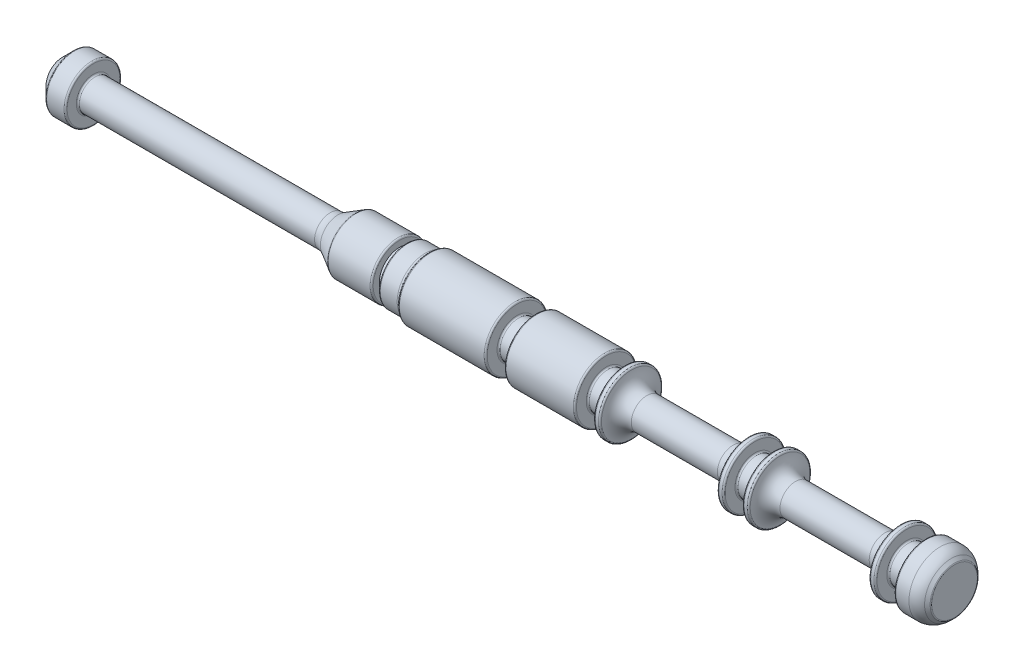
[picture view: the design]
ISO-10303-21;
HEADER;
FILE_DESCRIPTION(('STEP AP214'),'2;1');
FILE_NAME('part.step','',(''),(''),'','','');
FILE_SCHEMA(('AUTOMOTIVE_DESIGN { 1 0 10303 214 1 1 1 1 }'));
ENDSEC;
DATA;
#1=APPLICATION_CONTEXT('core data for automotive mechanical design processes');
#2=APPLICATION_PROTOCOL_DEFINITION('international standard','automotive_design',2000,#1);
#3=PRODUCT_CONTEXT('',#1,'mechanical');
#4=PRODUCT('Part','Part','',(#3));
#5=PRODUCT_RELATED_PRODUCT_CATEGORY('part','',(#4));
#6=PRODUCT_DEFINITION_FORMATION('','',#4);
#7=PRODUCT_DEFINITION_CONTEXT('part definition',#1,'design');
#8=PRODUCT_DEFINITION('design','',#6,#7);
#9=PRODUCT_DEFINITION_SHAPE('','',#8);
#10=(LENGTH_UNIT() NAMED_UNIT(*) SI_UNIT(.MILLI.,.METRE.));
#11=(NAMED_UNIT(*) PLANE_ANGLE_UNIT() SI_UNIT($,.RADIAN.));
#12=(NAMED_UNIT(*) SI_UNIT($,.STERADIAN.) SOLID_ANGLE_UNIT());
#13=UNCERTAINTY_MEASURE_WITH_UNIT(LENGTH_MEASURE(1.E-05),#10,'distance_accuracy_value','');
#14=(GEOMETRIC_REPRESENTATION_CONTEXT(3) GLOBAL_UNCERTAINTY_ASSIGNED_CONTEXT((#13)) GLOBAL_UNIT_ASSIGNED_CONTEXT((#10,
#11,#12)) REPRESENTATION_CONTEXT('',''));
#15=CARTESIAN_POINT('',(0.,0.,0.));
#16=DIRECTION('',(0.,0.,1.));
#17=DIRECTION('',(1.,0.,0.));
#18=AXIS2_PLACEMENT_3D('',#15,#16,#17);
#19=CARTESIAN_POINT('',(12.15,2.,0.));
#20=DIRECTION('',(1.,0.,0.));
#21=DIRECTION('',(0.,0.,-1.));
#22=AXIS2_PLACEMENT_3D('',#19,#20,#21);
#23=PLANE('',#22);
#24=CARTESIAN_POINT('',(12.15,0.,0.));
#25=DIRECTION('',(1.,0.,0.));
#26=DIRECTION('',(0.,0.,-1.));
#27=AXIS2_PLACEMENT_3D('',#24,#25,#26);
#28=CIRCLE('',#27,1.45857864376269);
#29=CARTESIAN_POINT('',(12.15,0.,-1.45857864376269));
#30=VERTEX_POINT('',#29);
#31=EDGE_CURVE('E103',#30,#30,#28,.T.);
#32=ORIENTED_EDGE('',*,*,#31,.T.);
#33=EDGE_LOOP('',(#32));
#34=FACE_BOUND('',#33,.T.);
#35=ADVANCED_FACE('F37',(#34),#23,.T.);
#36=CARTESIAN_POINT('',(0.,0.,0.));
#37=DIRECTION('',(1.,0.,0.));
#38=DIRECTION('',(0.,0.,-1.));
#39=AXIS2_PLACEMENT_3D('',#36,#37,#38);
#40=CYLINDRICAL_SURFACE('',#39,2.);
#41=CARTESIAN_POINT('',(11.2357864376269,0.,0.));
#42=DIRECTION('',(1.,0.,0.));
#43=DIRECTION('',(0.,0.,-1.));
#44=AXIS2_PLACEMENT_3D('',#41,#42,#43);
#45=CIRCLE('',#44,2.);
#46=CARTESIAN_POINT('',(11.2357864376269,0.,-2.));
#47=VERTEX_POINT('',#46);
#48=EDGE_CURVE('E44',#47,#47,#45,.F.);
#49=ORIENTED_EDGE('',*,*,#48,.T.);
#50=EDGE_LOOP('',(#49));
#51=FACE_BOUND('',#50,.T.);
#52=CARTESIAN_POINT('',(10.4,0.,0.));
#53=DIRECTION('',(-1.,0.,0.));
#54=DIRECTION('',(0.,0.,1.));
#55=AXIS2_PLACEMENT_3D('',#52,#53,#54);
#56=CIRCLE('',#55,2.);
#57=CARTESIAN_POINT('',(10.4,0.,2.));
#58=VERTEX_POINT('',#57);
#59=EDGE_CURVE('E52',#58,#58,#56,.F.);
#60=ORIENTED_EDGE('',*,*,#59,.T.);
#61=EDGE_LOOP('',(#60));
#62=FACE_BOUND('',#61,.T.);
#63=ADVANCED_FACE('F284',(#51,#62),#40,.T.);
#64=CARTESIAN_POINT('',(10.3,1.175,0.));
#65=DIRECTION('',(-1.,0.,0.));
#66=DIRECTION('',(0.,0.,1.));
#67=AXIS2_PLACEMENT_3D('',#64,#65,#66);
#68=PLANE('',#67);
#69=CARTESIAN_POINT('',(10.3,0.,0.));
#70=DIRECTION('',(-1.,0.,0.));
#71=DIRECTION('',(0.,0.,1.));
#72=AXIS2_PLACEMENT_3D('',#69,#70,#71);
#73=CIRCLE('',#72,1.9);
#74=CARTESIAN_POINT('',(10.3,0.,1.9));
#75=VERTEX_POINT('',#74);
#76=EDGE_CURVE('E48',#75,#75,#73,.T.);
#77=ORIENTED_EDGE('',*,*,#76,.T.);
#78=EDGE_LOOP('',(#77));
#79=FACE_BOUND('',#78,.T.);
#80=CARTESIAN_POINT('',(10.3,0.,0.));
#81=DIRECTION('',(-1.,0.,0.));
#82=DIRECTION('',(0.,0.,1.));
#83=AXIS2_PLACEMENT_3D('',#80,#81,#82);
#84=CIRCLE('',#83,1.275);
#85=CARTESIAN_POINT('',(10.3,0.,1.275));
#86=VERTEX_POINT('',#85);
#87=EDGE_CURVE('E185',#86,#86,#84,.F.);
#88=ORIENTED_EDGE('',*,*,#87,.T.);
#89=EDGE_LOOP('',(#88));
#90=FACE_BOUND('',#89,.T.);
#91=ADVANCED_FACE('F290',(#79,#90),#68,.T.);
#92=CARTESIAN_POINT('',(0.,0.,0.));
#93=DIRECTION('',(1.,0.,0.));
#94=DIRECTION('',(0.,0.,-1.));
#95=AXIS2_PLACEMENT_3D('',#92,#93,#94);
#96=CYLINDRICAL_SURFACE('',#95,1.175);
#97=CARTESIAN_POINT('',(9.2,0.,0.));
#98=DIRECTION('',(1.,0.,0.));
#99=DIRECTION('',(0.,0.,-1.));
#100=AXIS2_PLACEMENT_3D('',#97,#98,#99);
#101=CIRCLE('',#100,1.175);
#102=CARTESIAN_POINT('',(9.2,0.,-1.175));
#103=VERTEX_POINT('',#102);
#104=EDGE_CURVE('E191',#103,#103,#101,.T.);
#105=ORIENTED_EDGE('',*,*,#104,.T.);
#106=EDGE_LOOP('',(#105));
#107=FACE_BOUND('',#106,.T.);
#108=CARTESIAN_POINT('',(10.2,0.,0.));
#109=DIRECTION('',(-1.,0.,0.));
#110=DIRECTION('',(0.,0.,1.));
#111=AXIS2_PLACEMENT_3D('',#108,#109,#110);
#112=CIRCLE('',#111,1.175);
#113=CARTESIAN_POINT('',(10.2,0.,1.175));
#114=VERTEX_POINT('',#113);
#115=EDGE_CURVE('E194',#114,#114,#112,.T.);
#116=ORIENTED_EDGE('',*,*,#115,.T.);
#117=EDGE_LOOP('',(#116));
#118=FACE_BOUND('',#117,.T.);
#119=ADVANCED_FACE('F451',(#107,#118),#96,.T.);
#120=CARTESIAN_POINT('',(9.1,2.,0.));
#121=DIRECTION('',(1.,0.,0.));
#122=DIRECTION('',(0.,0.,-1.));
#123=AXIS2_PLACEMENT_3D('',#120,#121,#122);
#124=PLANE('',#123);
#125=CARTESIAN_POINT('',(9.1,0.,0.));
#126=DIRECTION('',(1.,0.,0.));
#127=DIRECTION('',(0.,0.,-1.));
#128=AXIS2_PLACEMENT_3D('',#125,#126,#127);
#129=CIRCLE('',#128,1.9);
#130=CARTESIAN_POINT('',(9.1,0.,-1.9));
#131=VERTEX_POINT('',#130);
#132=EDGE_CURVE('E115',#131,#131,#129,.T.);
#133=ORIENTED_EDGE('',*,*,#132,.T.);
#134=EDGE_LOOP('',(#133));
#135=FACE_BOUND('',#134,.T.);
#136=CARTESIAN_POINT('',(9.1,0.,0.));
#137=DIRECTION('',(1.,0.,0.));
#138=DIRECTION('',(0.,0.,-1.));
#139=AXIS2_PLACEMENT_3D('',#136,#137,#138);
#140=CIRCLE('',#139,1.275);
#141=CARTESIAN_POINT('',(9.1,0.,-1.275));
#142=VERTEX_POINT('',#141);
#143=EDGE_CURVE('E188',#142,#142,#140,.F.);
#144=ORIENTED_EDGE('',*,*,#143,.T.);
#145=EDGE_LOOP('',(#144));
#146=FACE_BOUND('',#145,.T.);
#147=ADVANCED_FACE('F457',(#135,#146),#124,.T.);
#148=CARTESIAN_POINT('',(0.,0.,0.));
#149=DIRECTION('',(1.,0.,0.));
#150=DIRECTION('',(0.,0.,-1.));
#151=AXIS2_PLACEMENT_3D('',#148,#149,#150);
#152=CYLINDRICAL_SURFACE('',#151,2.);
#153=CARTESIAN_POINT('',(9.,0.,0.));
#154=DIRECTION('',(1.,0.,0.));
#155=DIRECTION('',(0.,0.,-1.));
#156=AXIS2_PLACEMENT_3D('',#153,#154,#155);
#157=CIRCLE('',#156,2.);
#158=CARTESIAN_POINT('',(9.,0.,-2.));
#159=VERTEX_POINT('',#158);
#160=EDGE_CURVE('E109',#159,#159,#157,.F.);
#161=ORIENTED_EDGE('',*,*,#160,.T.);
#162=EDGE_LOOP('',(#161));
#163=FACE_BOUND('',#162,.T.);
#164=CARTESIAN_POINT('',(8.79544511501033,0.,0.));
#165=DIRECTION('',(-1.,0.,0.));
#166=DIRECTION('',(0.,0.,1.));
#167=AXIS2_PLACEMENT_3D('',#164,#165,#166);
#168=CIRCLE('',#167,2.);
#169=CARTESIAN_POINT('',(8.79544511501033,0.,2.));
#170=VERTEX_POINT('',#169);
#171=EDGE_CURVE('E112',#170,#170,#168,.F.);
#172=ORIENTED_EDGE('',*,*,#171,.T.);
#173=EDGE_LOOP('',(#172));
#174=FACE_BOUND('',#173,.T.);
#175=ADVANCED_FACE('F463',(#163,#174),#152,.T.);
#176=CARTESIAN_POINT('',(0.,0.,0.));
#177=DIRECTION('',(1.,0.,0.));
#178=DIRECTION('',(0.,0.,-1.));
#179=AXIS2_PLACEMENT_3D('',#176,#177,#178);
#180=CYLINDRICAL_SURFACE('',#179,0.999999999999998);
#181=CARTESIAN_POINT('',(7.7,0.,0.));
#182=DIRECTION('',(-1.,0.,0.));
#183=DIRECTION('',(0.,0.,1.));
#184=AXIS2_PLACEMENT_3D('',#181,#182,#183);
#185=CIRCLE('',#184,0.999999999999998);
#186=CARTESIAN_POINT('',(7.7,0.,0.999999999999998));
#187=VERTEX_POINT('',#186);
#188=EDGE_CURVE('E251',#187,#187,#185,.T.);
#189=ORIENTED_EDGE('',*,*,#188,.T.);
#190=EDGE_LOOP('',(#189));
#191=FACE_BOUND('',#190,.T.);
#192=CARTESIAN_POINT('',(2.,0.,0.));
#193=DIRECTION('',(1.,0.,0.));
#194=DIRECTION('',(0.,0.,-1.));
#195=AXIS2_PLACEMENT_3D('',#192,#193,#194);
#196=CIRCLE('',#195,0.999999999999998);
#197=CARTESIAN_POINT('',(2.,0.,-0.999999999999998));
#198=VERTEX_POINT('',#197);
#199=EDGE_CURVE('E254',#198,#198,#196,.T.);
#200=ORIENTED_EDGE('',*,*,#199,.T.);
#201=EDGE_LOOP('',(#200));
#202=FACE_BOUND('',#201,.T.);
#203=ADVANCED_FACE('F467',(#191,#202),#180,.T.);
#204=CARTESIAN_POINT('',(0.,0.,0.));
#205=DIRECTION('',(1.,0.,0.));
#206=DIRECTION('',(0.,0.,-1.));
#207=AXIS2_PLACEMENT_3D('',#204,#205,#206);
#208=CYLINDRICAL_SURFACE('',#207,2.);
#209=CARTESIAN_POINT('',(0.904554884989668,0.,0.));
#210=DIRECTION('',(-1.,0.,0.));
#211=DIRECTION('',(0.,0.,1.));
#212=AXIS2_PLACEMENT_3D('',#209,#210,#211);
#213=CIRCLE('',#212,2.);
#214=CARTESIAN_POINT('',(0.904554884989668,0.,2.));
#215=VERTEX_POINT('',#214);
#216=EDGE_CURVE('E121',#215,#215,#213,.T.);
#217=ORIENTED_EDGE('',*,*,#216,.T.);
#218=EDGE_LOOP('',(#217));
#219=FACE_BOUND('',#218,.T.);
#220=CARTESIAN_POINT('',(0.7,0.,0.));
#221=DIRECTION('',(-1.,0.,0.));
#222=DIRECTION('',(0.,0.,1.));
#223=AXIS2_PLACEMENT_3D('',#220,#221,#222);
#224=CIRCLE('',#223,2.);
#225=CARTESIAN_POINT('',(0.7,0.,2.));
#226=VERTEX_POINT('',#225);
#227=EDGE_CURVE('E124',#226,#226,#224,.F.);
#228=ORIENTED_EDGE('',*,*,#227,.T.);
#229=EDGE_LOOP('',(#228));
#230=FACE_BOUND('',#229,.T.);
#231=ADVANCED_FACE('F471',(#219,#230),#208,.T.);
#232=CARTESIAN_POINT('',(0.6,1.175,0.));
#233=DIRECTION('',(-1.,0.,0.));
#234=DIRECTION('',(0.,0.,1.));
#235=AXIS2_PLACEMENT_3D('',#232,#233,#234);
#236=PLANE('',#235);
#237=CARTESIAN_POINT('',(0.6,0.,0.));
#238=DIRECTION('',(-1.,0.,0.));
#239=DIRECTION('',(0.,0.,1.));
#240=AXIS2_PLACEMENT_3D('',#237,#238,#239);
#241=CIRCLE('',#240,1.9);
#242=CARTESIAN_POINT('',(0.6,0.,1.9));
#243=VERTEX_POINT('',#242);
#244=EDGE_CURVE('E118',#243,#243,#241,.T.);
#245=ORIENTED_EDGE('',*,*,#244,.T.);
#246=EDGE_LOOP('',(#245));
#247=FACE_BOUND('',#246,.T.);
#248=CARTESIAN_POINT('',(0.6,0.,0.));
#249=DIRECTION('',(-1.,0.,0.));
#250=DIRECTION('',(0.,0.,1.));
#251=AXIS2_PLACEMENT_3D('',#248,#249,#250);
#252=CIRCLE('',#251,1.275);
#253=CARTESIAN_POINT('',(0.6,0.,1.275));
#254=VERTEX_POINT('',#253);
#255=EDGE_CURVE('E197',#254,#254,#252,.F.);
#256=ORIENTED_EDGE('',*,*,#255,.T.);
#257=EDGE_LOOP('',(#256));
#258=FACE_BOUND('',#257,.T.);
#259=ADVANCED_FACE('F475',(#247,#258),#236,.T.);
#260=CARTESIAN_POINT('',(0.,0.,0.));
#261=DIRECTION('',(1.,0.,0.));
#262=DIRECTION('',(0.,0.,-1.));
#263=AXIS2_PLACEMENT_3D('',#260,#261,#262);
#264=CYLINDRICAL_SURFACE('',#263,1.175);
#265=CARTESIAN_POINT('',(-0.5,0.,0.));
#266=DIRECTION('',(1.,0.,0.));
#267=DIRECTION('',(0.,0.,-1.));
#268=AXIS2_PLACEMENT_3D('',#265,#266,#267);
#269=CIRCLE('',#268,1.175);
#270=CARTESIAN_POINT('',(-0.5,0.,-1.175));
#271=VERTEX_POINT('',#270);
#272=EDGE_CURVE('E203',#271,#271,#269,.T.);
#273=ORIENTED_EDGE('',*,*,#272,.T.);
#274=EDGE_LOOP('',(#273));
#275=FACE_BOUND('',#274,.T.);
#276=CARTESIAN_POINT('',(0.5,0.,0.));
#277=DIRECTION('',(-1.,0.,0.));
#278=DIRECTION('',(0.,0.,1.));
#279=AXIS2_PLACEMENT_3D('',#276,#277,#278);
#280=CIRCLE('',#279,1.175);
#281=CARTESIAN_POINT('',(0.5,0.,1.175));
#282=VERTEX_POINT('',#281);
#283=EDGE_CURVE('E206',#282,#282,#280,.T.);
#284=ORIENTED_EDGE('',*,*,#283,.T.);
#285=EDGE_LOOP('',(#284));
#286=FACE_BOUND('',#285,.T.);
#287=ADVANCED_FACE('F479',(#275,#286),#264,.T.);
#288=CARTESIAN_POINT('',(-0.6,2.,0.));
#289=DIRECTION('',(1.,0.,0.));
#290=DIRECTION('',(0.,0.,-1.));
#291=AXIS2_PLACEMENT_3D('',#288,#289,#290);
#292=PLANE('',#291);
#293=CARTESIAN_POINT('',(-0.6,0.,0.));
#294=DIRECTION('',(1.,0.,0.));
#295=DIRECTION('',(0.,0.,-1.));
#296=AXIS2_PLACEMENT_3D('',#293,#294,#295);
#297=CIRCLE('',#296,1.9);
#298=CARTESIAN_POINT('',(-0.6,0.,-1.9));
#299=VERTEX_POINT('',#298);
#300=EDGE_CURVE('E139',#299,#299,#297,.T.);
#301=ORIENTED_EDGE('',*,*,#300,.T.);
#302=EDGE_LOOP('',(#301));
#303=FACE_BOUND('',#302,.T.);
#304=CARTESIAN_POINT('',(-0.6,0.,0.));
#305=DIRECTION('',(1.,0.,0.));
#306=DIRECTION('',(0.,0.,-1.));
#307=AXIS2_PLACEMENT_3D('',#304,#305,#306);
#308=CIRCLE('',#307,1.275);
#309=CARTESIAN_POINT('',(-0.6,0.,-1.275));
#310=VERTEX_POINT('',#309);
#311=EDGE_CURVE('E200',#310,#310,#308,.F.);
#312=ORIENTED_EDGE('',*,*,#311,.T.);
#313=EDGE_LOOP('',(#312));
#314=FACE_BOUND('',#313,.T.);
#315=ADVANCED_FACE('F483',(#303,#314),#292,.T.);
#316=CARTESIAN_POINT('',(0.,0.,0.));
#317=DIRECTION('',(1.,0.,0.));
#318=DIRECTION('',(0.,0.,-1.));
#319=AXIS2_PLACEMENT_3D('',#316,#317,#318);
#320=CYLINDRICAL_SURFACE('',#319,2.);
#321=CARTESIAN_POINT('',(-0.7,0.,0.));
#322=DIRECTION('',(1.,0.,0.));
#323=DIRECTION('',(0.,0.,-1.));
#324=AXIS2_PLACEMENT_3D('',#321,#322,#323);
#325=CIRCLE('',#324,2.);
#326=CARTESIAN_POINT('',(-0.7,0.,-2.));
#327=VERTEX_POINT('',#326);
#328=EDGE_CURVE('E133',#327,#327,#325,.F.);
#329=ORIENTED_EDGE('',*,*,#328,.T.);
#330=EDGE_LOOP('',(#329));
#331=FACE_BOUND('',#330,.T.);
#332=CARTESIAN_POINT('',(-0.904554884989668,0.,0.));
#333=DIRECTION('',(-1.,0.,0.));
#334=DIRECTION('',(0.,0.,1.));
#335=AXIS2_PLACEMENT_3D('',#332,#333,#334);
#336=CIRCLE('',#335,2.);
#337=CARTESIAN_POINT('',(-0.904554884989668,0.,2.));
#338=VERTEX_POINT('',#337);
#339=EDGE_CURVE('E136',#338,#338,#336,.F.);
#340=ORIENTED_EDGE('',*,*,#339,.T.);
#341=EDGE_LOOP('',(#340));
#342=FACE_BOUND('',#341,.T.);
#343=ADVANCED_FACE('F487',(#331,#342),#320,.T.);
#344=CARTESIAN_POINT('',(0.,0.,0.));
#345=DIRECTION('',(1.,0.,0.));
#346=DIRECTION('',(0.,0.,-1.));
#347=AXIS2_PLACEMENT_3D('',#344,#345,#346);
#348=CYLINDRICAL_SURFACE('',#347,0.999999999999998);
#349=CARTESIAN_POINT('',(-2.,0.,0.));
#350=DIRECTION('',(-1.,0.,0.));
#351=DIRECTION('',(0.,0.,1.));
#352=AXIS2_PLACEMENT_3D('',#349,#350,#351);
#353=CIRCLE('',#352,0.999999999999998);
#354=CARTESIAN_POINT('',(-2.,0.,0.999999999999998));
#355=VERTEX_POINT('',#354);
#356=EDGE_CURVE('E245',#355,#355,#353,.T.);
#357=ORIENTED_EDGE('',*,*,#356,.T.);
#358=EDGE_LOOP('',(#357));
#359=FACE_BOUND('',#358,.T.);
#360=CARTESIAN_POINT('',(-7.5,0.,0.));
#361=DIRECTION('',(1.,0.,0.));
#362=DIRECTION('',(0.,0.,-1.));
#363=AXIS2_PLACEMENT_3D('',#360,#361,#362);
#364=CIRCLE('',#363,0.999999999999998);
#365=CARTESIAN_POINT('',(-7.5,0.,-0.999999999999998));
#366=VERTEX_POINT('',#365);
#367=EDGE_CURVE('E248',#366,#366,#364,.T.);
#368=ORIENTED_EDGE('',*,*,#367,.T.);
#369=EDGE_LOOP('',(#368));
#370=FACE_BOUND('',#369,.T.);
#371=ADVANCED_FACE('F491',(#359,#370),#348,.T.);
#372=CARTESIAN_POINT('',(0.,0.,0.));
#373=DIRECTION('',(1.,0.,0.));
#374=DIRECTION('',(0.,0.,-1.));
#375=AXIS2_PLACEMENT_3D('',#372,#373,#374);
#376=CYLINDRICAL_SURFACE('',#375,2.);
#377=CARTESIAN_POINT('',(-8.59544511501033,0.,0.));
#378=DIRECTION('',(-1.,0.,0.));
#379=DIRECTION('',(0.,0.,1.));
#380=AXIS2_PLACEMENT_3D('',#377,#378,#379);
#381=CIRCLE('',#380,2.);
#382=CARTESIAN_POINT('',(-8.59544511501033,0.,2.));
#383=VERTEX_POINT('',#382);
#384=EDGE_CURVE('E145',#383,#383,#381,.T.);
#385=ORIENTED_EDGE('',*,*,#384,.T.);
#386=EDGE_LOOP('',(#385));
#387=FACE_BOUND('',#386,.T.);
#388=CARTESIAN_POINT('',(-8.8,0.,0.));
#389=DIRECTION('',(-1.,0.,0.));
#390=DIRECTION('',(0.,0.,1.));
#391=AXIS2_PLACEMENT_3D('',#388,#389,#390);
#392=CIRCLE('',#391,2.);
#393=CARTESIAN_POINT('',(-8.8,0.,2.));
#394=VERTEX_POINT('',#393);
#395=EDGE_CURVE('E148',#394,#394,#392,.F.);
#396=ORIENTED_EDGE('',*,*,#395,.T.);
#397=EDGE_LOOP('',(#396));
#398=FACE_BOUND('',#397,.T.);
#399=ADVANCED_FACE('F495',(#387,#398),#376,.T.);
#400=CARTESIAN_POINT('',(-8.9,1.175,0.));
#401=DIRECTION('',(-1.,0.,0.));
#402=DIRECTION('',(0.,0.,1.));
#403=AXIS2_PLACEMENT_3D('',#400,#401,#402);
#404=PLANE('',#403);
#405=CARTESIAN_POINT('',(-8.9,0.,0.));
#406=DIRECTION('',(-1.,0.,0.));
#407=DIRECTION('',(0.,0.,1.));
#408=AXIS2_PLACEMENT_3D('',#405,#406,#407);
#409=CIRCLE('',#408,1.9);
#410=CARTESIAN_POINT('',(-8.9,0.,1.9));
#411=VERTEX_POINT('',#410);
#412=EDGE_CURVE('E142',#411,#411,#409,.T.);
#413=ORIENTED_EDGE('',*,*,#412,.T.);
#414=EDGE_LOOP('',(#413));
#415=FACE_BOUND('',#414,.T.);
#416=CARTESIAN_POINT('',(-8.9,0.,0.));
#417=DIRECTION('',(-1.,0.,0.));
#418=DIRECTION('',(0.,0.,1.));
#419=AXIS2_PLACEMENT_3D('',#416,#417,#418);
#420=CIRCLE('',#419,1.275);
#421=CARTESIAN_POINT('',(-8.9,0.,1.275));
#422=VERTEX_POINT('',#421);
#423=EDGE_CURVE('E209',#422,#422,#420,.F.);
#424=ORIENTED_EDGE('',*,*,#423,.T.);
#425=EDGE_LOOP('',(#424));
#426=FACE_BOUND('',#425,.T.);
#427=ADVANCED_FACE('F499',(#415,#426),#404,.T.);
#428=CARTESIAN_POINT('',(0.,0.,0.));
#429=DIRECTION('',(1.,0.,0.));
#430=DIRECTION('',(0.,0.,-1.));
#431=AXIS2_PLACEMENT_3D('',#428,#429,#430);
#432=CYLINDRICAL_SURFACE('',#431,1.175);
#433=CARTESIAN_POINT('',(-10.,0.,0.));
#434=DIRECTION('',(1.,0.,0.));
#435=DIRECTION('',(0.,0.,-1.));
#436=AXIS2_PLACEMENT_3D('',#433,#434,#435);
#437=CIRCLE('',#436,1.175);
#438=CARTESIAN_POINT('',(-10.,0.,-1.175));
#439=VERTEX_POINT('',#438);
#440=EDGE_CURVE('E215',#439,#439,#437,.T.);
#441=ORIENTED_EDGE('',*,*,#440,.T.);
#442=EDGE_LOOP('',(#441));
#443=FACE_BOUND('',#442,.T.);
#444=CARTESIAN_POINT('',(-9.,0.,0.));
#445=DIRECTION('',(-1.,0.,0.));
#446=DIRECTION('',(0.,0.,1.));
#447=AXIS2_PLACEMENT_3D('',#444,#445,#446);
#448=CIRCLE('',#447,1.175);
#449=CARTESIAN_POINT('',(-9.,0.,1.175));
#450=VERTEX_POINT('',#449);
#451=EDGE_CURVE('E218',#450,#450,#448,.T.);
#452=ORIENTED_EDGE('',*,*,#451,.T.);
#453=EDGE_LOOP('',(#452));
#454=FACE_BOUND('',#453,.T.);
#455=ADVANCED_FACE('F503',(#443,#454),#432,.T.);
#456=CARTESIAN_POINT('',(-10.1,2.,0.));
#457=DIRECTION('',(1.,0.,0.));
#458=DIRECTION('',(0.,0.,-1.));
#459=AXIS2_PLACEMENT_3D('',#456,#457,#458);
#460=PLANE('',#459);
#461=CARTESIAN_POINT('',(-10.1,0.,0.));
#462=DIRECTION('',(1.,0.,0.));
#463=DIRECTION('',(0.,0.,-1.));
#464=AXIS2_PLACEMENT_3D('',#461,#462,#463);
#465=CIRCLE('',#464,1.9);
#466=CARTESIAN_POINT('',(-10.1,0.,-1.9));
#467=VERTEX_POINT('',#466);
#468=EDGE_CURVE('E163',#467,#467,#465,.T.);
#469=ORIENTED_EDGE('',*,*,#468,.T.);
#470=EDGE_LOOP('',(#469));
#471=FACE_BOUND('',#470,.T.);
#472=CARTESIAN_POINT('',(-10.1,0.,0.));
#473=DIRECTION('',(1.,0.,0.));
#474=DIRECTION('',(0.,0.,-1.));
#475=AXIS2_PLACEMENT_3D('',#472,#473,#474);
#476=CIRCLE('',#475,1.275);
#477=CARTESIAN_POINT('',(-10.1,0.,-1.275));
#478=VERTEX_POINT('',#477);
#479=EDGE_CURVE('E212',#478,#478,#476,.F.);
#480=ORIENTED_EDGE('',*,*,#479,.T.);
#481=EDGE_LOOP('',(#480));
#482=FACE_BOUND('',#481,.T.);
#483=ADVANCED_FACE('F507',(#471,#482),#460,.T.);
#484=CARTESIAN_POINT('',(0.,0.,0.));
#485=DIRECTION('',(1.,0.,0.));
#486=DIRECTION('',(0.,0.,-1.));
#487=AXIS2_PLACEMENT_3D('',#484,#485,#486);
#488=CYLINDRICAL_SURFACE('',#487,2.);
#489=CARTESIAN_POINT('',(-10.2,0.,0.));
#490=DIRECTION('',(1.,0.,0.));
#491=DIRECTION('',(0.,0.,-1.));
#492=AXIS2_PLACEMENT_3D('',#489,#490,#491);
#493=CIRCLE('',#492,2.);
#494=CARTESIAN_POINT('',(-10.2,0.,-2.));
#495=VERTEX_POINT('',#494);
#496=EDGE_CURVE('E157',#495,#495,#493,.F.);
#497=ORIENTED_EDGE('',*,*,#496,.T.);
#498=EDGE_LOOP('',(#497));
#499=FACE_BOUND('',#498,.T.);
#500=CARTESIAN_POINT('',(-14.5,0.,0.));
#501=DIRECTION('',(-1.,0.,0.));
#502=DIRECTION('',(0.,0.,1.));
#503=AXIS2_PLACEMENT_3D('',#500,#501,#502);
#504=CIRCLE('',#503,2.);
#505=CARTESIAN_POINT('',(-14.5,0.,2.));
#506=VERTEX_POINT('',#505);
#507=EDGE_CURVE('E160',#506,#506,#504,.F.);
#508=ORIENTED_EDGE('',*,*,#507,.T.);
#509=EDGE_LOOP('',(#508));
#510=FACE_BOUND('',#509,.T.);
#511=ADVANCED_FACE('F511',(#499,#510),#488,.T.);
#512=CARTESIAN_POINT('',(-14.6,1.175,0.));
#513=DIRECTION('',(-1.,0.,0.));
#514=DIRECTION('',(0.,0.,1.));
#515=AXIS2_PLACEMENT_3D('',#512,#513,#514);
#516=PLANE('',#515);
#517=CARTESIAN_POINT('',(-14.6,0.,0.));
#518=DIRECTION('',(-1.,0.,0.));
#519=DIRECTION('',(0.,0.,1.));
#520=AXIS2_PLACEMENT_3D('',#517,#518,#519);
#521=CIRCLE('',#520,1.9);
#522=CARTESIAN_POINT('',(-14.6,0.,1.9));
#523=VERTEX_POINT('',#522);
#524=EDGE_CURVE('E154',#523,#523,#521,.T.);
#525=ORIENTED_EDGE('',*,*,#524,.T.);
#526=EDGE_LOOP('',(#525));
#527=FACE_BOUND('',#526,.T.);
#528=CARTESIAN_POINT('',(-14.6,0.,0.));
#529=DIRECTION('',(-1.,0.,0.));
#530=DIRECTION('',(0.,0.,1.));
#531=AXIS2_PLACEMENT_3D('',#528,#529,#530);
#532=CIRCLE('',#531,1.275);
#533=CARTESIAN_POINT('',(-14.6,0.,1.275));
#534=VERTEX_POINT('',#533);
#535=EDGE_CURVE('E221',#534,#534,#532,.F.);
#536=ORIENTED_EDGE('',*,*,#535,.T.);
#537=EDGE_LOOP('',(#536));
#538=FACE_BOUND('',#537,.T.);
#539=ADVANCED_FACE('F515',(#527,#538),#516,.T.);
#540=CARTESIAN_POINT('',(0.,0.,0.));
#541=DIRECTION('',(1.,0.,0.));
#542=DIRECTION('',(0.,0.,-1.));
#543=AXIS2_PLACEMENT_3D('',#540,#541,#542);
#544=CYLINDRICAL_SURFACE('',#543,1.175);
#545=CARTESIAN_POINT('',(-15.7,0.,0.));
#546=DIRECTION('',(1.,0.,0.));
#547=DIRECTION('',(0.,0.,-1.));
#548=AXIS2_PLACEMENT_3D('',#545,#546,#547);
#549=CIRCLE('',#548,1.175);
#550=CARTESIAN_POINT('',(-15.7,0.,-1.175));
#551=VERTEX_POINT('',#550);
#552=EDGE_CURVE('E227',#551,#551,#549,.T.);
#553=ORIENTED_EDGE('',*,*,#552,.T.);
#554=EDGE_LOOP('',(#553));
#555=FACE_BOUND('',#554,.T.);
#556=CARTESIAN_POINT('',(-14.7,0.,0.));
#557=DIRECTION('',(-1.,0.,0.));
#558=DIRECTION('',(0.,0.,1.));
#559=AXIS2_PLACEMENT_3D('',#556,#557,#558);
#560=CIRCLE('',#559,1.175);
#561=CARTESIAN_POINT('',(-14.7,0.,1.175));
#562=VERTEX_POINT('',#561);
#563=EDGE_CURVE('E230',#562,#562,#560,.T.);
#564=ORIENTED_EDGE('',*,*,#563,.T.);
#565=EDGE_LOOP('',(#564));
#566=FACE_BOUND('',#565,.T.);
#567=ADVANCED_FACE('F519',(#555,#566),#544,.T.);
#568=CARTESIAN_POINT('',(-15.8,2.,0.));
#569=DIRECTION('',(1.,0.,0.));
#570=DIRECTION('',(0.,0.,-1.));
#571=AXIS2_PLACEMENT_3D('',#568,#569,#570);
#572=PLANE('',#571);
#573=CARTESIAN_POINT('',(-15.8,0.,0.));
#574=DIRECTION('',(1.,0.,0.));
#575=DIRECTION('',(0.,0.,-1.));
#576=AXIS2_PLACEMENT_3D('',#573,#574,#575);
#577=CIRCLE('',#576,1.9);
#578=CARTESIAN_POINT('',(-15.8,0.,-1.9));
#579=VERTEX_POINT('',#578);
#580=EDGE_CURVE('E57',#579,#579,#577,.T.);
#581=ORIENTED_EDGE('',*,*,#580,.T.);
#582=EDGE_LOOP('',(#581));
#583=FACE_BOUND('',#582,.T.);
#584=CARTESIAN_POINT('',(-15.8,0.,0.));
#585=DIRECTION('',(1.,0.,0.));
#586=DIRECTION('',(0.,0.,-1.));
#587=AXIS2_PLACEMENT_3D('',#584,#585,#586);
#588=CIRCLE('',#587,1.275);
#589=CARTESIAN_POINT('',(-15.8,0.,-1.275));
#590=VERTEX_POINT('',#589);
#591=EDGE_CURVE('E224',#590,#590,#588,.F.);
#592=ORIENTED_EDGE('',*,*,#591,.T.);
#593=EDGE_LOOP('',(#592));
#594=FACE_BOUND('',#593,.T.);
#595=ADVANCED_FACE('F523',(#583,#594),#572,.T.);
#596=CARTESIAN_POINT('',(0.,0.,0.));
#597=DIRECTION('',(1.,0.,0.));
#598=DIRECTION('',(0.,0.,-1.));
#599=AXIS2_PLACEMENT_3D('',#596,#597,#598);
#600=CYLINDRICAL_SURFACE('',#599,2.);
#601=CARTESIAN_POINT('',(-21.3085786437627,0.,0.));
#602=DIRECTION('',(-1.,0.,0.));
#603=DIRECTION('',(0.,0.,1.));
#604=AXIS2_PLACEMENT_3D('',#601,#602,#603);
#605=CIRCLE('',#604,2.);
#606=CARTESIAN_POINT('',(-21.3085786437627,0.,2.));
#607=VERTEX_POINT('',#606);
#608=EDGE_CURVE('E170',#607,#607,#605,.F.);
#609=ORIENTED_EDGE('',*,*,#608,.T.);
#610=EDGE_LOOP('',(#609));
#611=FACE_BOUND('',#610,.T.);
#612=CARTESIAN_POINT('',(-15.9,0.,0.));
#613=DIRECTION('',(1.,0.,0.));
#614=DIRECTION('',(0.,0.,-1.));
#615=AXIS2_PLACEMENT_3D('',#612,#613,#614);
#616=CIRCLE('',#615,2.);
#617=CARTESIAN_POINT('',(-15.9,0.,-2.));
#618=VERTEX_POINT('',#617);
#619=EDGE_CURVE('E174',#618,#618,#616,.F.);
#620=ORIENTED_EDGE('',*,*,#619,.T.);
#621=EDGE_LOOP('',(#620));
#622=FACE_BOUND('',#621,.T.);
#623=ADVANCED_FACE('F527',(#611,#622),#600,.T.);
#624=CARTESIAN_POINT('',(-21.35,0.,0.));
#625=DIRECTION('',(1.,0.,0.));
#626=DIRECTION('',(0.,0.,-1.));
#627=AXIS2_PLACEMENT_3D('',#624,#625,#626);
#628=CONICAL_SURFACE('',#627,2.,0.78539816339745);
#629=CARTESIAN_POINT('',(-21.3792893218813,0.,0.));
#630=DIRECTION('',(-1.,0.,0.));
#631=DIRECTION('',(0.,0.,1.));
#632=AXIS2_PLACEMENT_3D('',#629,#630,#631);
#633=CIRCLE('',#632,1.97071067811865);
#634=CARTESIAN_POINT('',(-21.3792893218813,0.,1.97071067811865));
#635=VERTEX_POINT('',#634);
#636=EDGE_CURVE('E166',#635,#635,#633,.T.);
#637=ORIENTED_EDGE('',*,*,#636,.T.);
#638=EDGE_LOOP('',(#637));
#639=FACE_BOUND('',#638,.T.);
#640=CARTESIAN_POINT('',(-21.4908391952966,0.,0.));
#641=DIRECTION('',(1.,0.,0.));
#642=DIRECTION('',(0.,0.,-1.));
#643=AXIS2_PLACEMENT_3D('',#640,#641,#642);
#644=CIRCLE('',#643,1.85916080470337);
#645=CARTESIAN_POINT('',(-21.4908391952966,0.,-1.85916080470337));
#646=VERTEX_POINT('',#645);
#647=EDGE_CURVE('E181',#646,#646,#644,.T.);
#648=ORIENTED_EDGE('',*,*,#647,.T.);
#649=EDGE_LOOP('',(#648));
#650=FACE_BOUND('',#649,.T.);
#651=ADVANCED_FACE('F531',(#639,#650),#628,.T.);
#652=CARTESIAN_POINT('',(0.,0.,0.));
#653=DIRECTION('',(1.,0.,0.));
#654=DIRECTION('',(0.,0.,-1.));
#655=AXIS2_PLACEMENT_3D('',#652,#653,#654);
#656=CYLINDRICAL_SURFACE('',#655,1.7859375);
#657=CARTESIAN_POINT('',(-22.75,0.,0.));
#658=DIRECTION('',(-1.,0.,0.));
#659=DIRECTION('',(0.,0.,1.));
#660=AXIS2_PLACEMENT_3D('',#657,#658,#659);
#661=CIRCLE('',#660,1.7859375);
#662=CARTESIAN_POINT('',(-22.75,0.,1.7859375));
#663=VERTEX_POINT('',#662);
#664=EDGE_CURVE('E64',#663,#663,#661,.F.);
#665=ORIENTED_EDGE('',*,*,#664,.T.);
#666=EDGE_LOOP('',(#665));
#667=FACE_BOUND('',#666,.T.);
#668=CARTESIAN_POINT('',(-21.6676158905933,0.,0.));
#669=DIRECTION('',(1.,0.,0.));
#670=DIRECTION('',(0.,0.,-1.));
#671=AXIS2_PLACEMENT_3D('',#668,#669,#670);
#672=CIRCLE('',#671,1.7859375);
#673=CARTESIAN_POINT('',(-21.6676158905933,0.,-1.7859375));
#674=VERTEX_POINT('',#673);
#675=EDGE_CURVE('E177',#674,#674,#672,.F.);
#676=ORIENTED_EDGE('',*,*,#675,.T.);
#677=EDGE_LOOP('',(#676));
#678=FACE_BOUND('',#677,.T.);
#679=ADVANCED_FACE('F535',(#667,#678),#656,.T.);
#680=CARTESIAN_POINT('',(-22.85,1.7859375,0.));
#681=DIRECTION('',(-1.,0.,0.));
#682=DIRECTION('',(0.,0.,1.));
#683=AXIS2_PLACEMENT_3D('',#680,#681,#682);
#684=PLANE('',#683);
#685=CARTESIAN_POINT('',(-22.85,0.,0.));
#686=DIRECTION('',(-1.,0.,0.));
#687=DIRECTION('',(0.,0.,1.));
#688=AXIS2_PLACEMENT_3D('',#685,#686,#687);
#689=CIRCLE('',#688,1.6859375);
#690=CARTESIAN_POINT('',(-22.85,0.,1.6859375));
#691=VERTEX_POINT('',#690);
#692=EDGE_CURVE('E60',#691,#691,#689,.T.);
#693=ORIENTED_EDGE('',*,*,#692,.T.);
#694=EDGE_LOOP('',(#693));
#695=FACE_BOUND('',#694,.T.);
#696=CARTESIAN_POINT('',(-22.85,0.,0.));
#697=DIRECTION('',(1.,0.,0.));
#698=DIRECTION('',(0.,0.,-1.));
#699=AXIS2_PLACEMENT_3D('',#696,#697,#698);
#700=CIRCLE('',#699,1.2954);
#701=CARTESIAN_POINT('',(-22.85,0.,-1.2954));
#702=VERTEX_POINT('',#701);
#703=EDGE_CURVE('E257',#702,#702,#700,.T.);
#704=ORIENTED_EDGE('',*,*,#703,.T.);
#705=EDGE_LOOP('',(#704));
#706=FACE_BOUND('',#705,.T.);
#707=ADVANCED_FACE('F281',(#695,#706),#684,.T.);
#708=CARTESIAN_POINT('',(0.,0.,0.));
#709=DIRECTION('',(1.,0.,0.));
#710=DIRECTION('',(0.,0.,-1.));
#711=AXIS2_PLACEMENT_3D('',#708,#709,#710);
#712=CYLINDRICAL_SURFACE('',#711,1.2954);
#713=CARTESIAN_POINT('',(-23.3,0.,0.));
#714=DIRECTION('',(1.,0.,0.));
#715=DIRECTION('',(0.,0.,-1.));
#716=AXIS2_PLACEMENT_3D('',#713,#714,#715);
#717=CIRCLE('',#716,1.2954);
#718=CARTESIAN_POINT('',(-23.3,0.,-1.2954));
#719=VERTEX_POINT('',#718);
#720=EDGE_CURVE('E261',#719,#719,#717,.T.);
#721=ORIENTED_EDGE('',*,*,#720,.T.);
#722=EDGE_LOOP('',(#721));
#723=FACE_BOUND('',#722,.T.);
#724=ORIENTED_EDGE('',*,*,#703,.F.);
#725=EDGE_LOOP('',(#724));
#726=FACE_BOUND('',#725,.T.);
#727=ADVANCED_FACE('F266',(#723,#726),#712,.T.);
#728=CARTESIAN_POINT('',(-23.3,1.2954,0.));
#729=DIRECTION('',(1.,0.,0.));
#730=DIRECTION('',(0.,0.,-1.));
#731=AXIS2_PLACEMENT_3D('',#728,#729,#730);
#732=PLANE('',#731);
#733=CARTESIAN_POINT('',(-23.3,0.,0.));
#734=DIRECTION('',(1.,0.,0.));
#735=DIRECTION('',(0.,0.,-1.));
#736=AXIS2_PLACEMENT_3D('',#733,#734,#735);
#737=CIRCLE('',#736,1.6859375);
#738=CARTESIAN_POINT('',(-23.3,0.,-1.6859375));
#739=VERTEX_POINT('',#738);
#740=EDGE_CURVE('E68',#739,#739,#737,.T.);
#741=ORIENTED_EDGE('',*,*,#740,.T.);
#742=EDGE_LOOP('',(#741));
#743=FACE_BOUND('',#742,.T.);
#744=ORIENTED_EDGE('',*,*,#720,.F.);
#745=EDGE_LOOP('',(#744));
#746=FACE_BOUND('',#745,.T.);
#747=ADVANCED_FACE('F269',(#743,#746),#732,.T.);
#748=CARTESIAN_POINT('',(0.,0.,0.));
#749=DIRECTION('',(1.,0.,0.));
#750=DIRECTION('',(0.,0.,-1.));
#751=AXIS2_PLACEMENT_3D('',#748,#749,#750);
#752=CYLINDRICAL_SURFACE('',#751,1.7859375);
#753=CARTESIAN_POINT('',(-26.0732050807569,0.,0.));
#754=DIRECTION('',(-1.,0.,0.));
#755=DIRECTION('',(0.,0.,1.));
#756=AXIS2_PLACEMENT_3D('',#753,#754,#755);
#757=CIRCLE('',#756,1.7859375);
#758=CARTESIAN_POINT('',(-26.0732050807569,0.,1.7859375));
#759=VERTEX_POINT('',#758);
#760=EDGE_CURVE('E84',#759,#759,#757,.F.);
#761=ORIENTED_EDGE('',*,*,#760,.T.);
#762=EDGE_LOOP('',(#761));
#763=FACE_BOUND('',#762,.T.);
#764=CARTESIAN_POINT('',(-23.4,0.,0.));
#765=DIRECTION('',(1.,0.,0.));
#766=DIRECTION('',(0.,0.,-1.));
#767=AXIS2_PLACEMENT_3D('',#764,#765,#766);
#768=CIRCLE('',#767,1.7859375);
#769=CARTESIAN_POINT('',(-23.4,0.,-1.7859375));
#770=VERTEX_POINT('',#769);
#771=EDGE_CURVE('E87',#770,#770,#768,.F.);
#772=ORIENTED_EDGE('',*,*,#771,.T.);
#773=EDGE_LOOP('',(#772));
#774=FACE_BOUND('',#773,.T.);
#775=ADVANCED_FACE('F271',(#763,#774),#752,.T.);
#776=CARTESIAN_POINT('',(-26.1,0.,0.));
#777=DIRECTION('',(1.,0.,0.));
#778=DIRECTION('',(0.,0.,-1.));
#779=AXIS2_PLACEMENT_3D('',#776,#777,#778);
#780=CONICAL_SURFACE('',#779,1.7859375,0.5235987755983);
#781=CARTESIAN_POINT('',(-26.1232050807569,0.,0.));
#782=DIRECTION('',(-1.,0.,0.));
#783=DIRECTION('',(0.,0.,1.));
#784=AXIS2_PLACEMENT_3D('',#781,#782,#783);
#785=CIRCLE('',#784,1.77254004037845);
#786=CARTESIAN_POINT('',(-26.1232050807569,0.,1.77254004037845));
#787=VERTEX_POINT('',#786);
#788=EDGE_CURVE('E81',#787,#787,#785,.T.);
#789=ORIENTED_EDGE('',*,*,#788,.T.);
#790=EDGE_LOOP('',(#789));
#791=FACE_BOUND('',#790,.T.);
#792=CARTESIAN_POINT('',(-27.2292328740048,0.,0.));
#793=DIRECTION('',(1.,0.,0.));
#794=DIRECTION('',(0.,0.,-1.));
#795=AXIS2_PLACEMENT_3D('',#792,#793,#794);
#796=CIRCLE('',#795,1.13397459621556);
#797=CARTESIAN_POINT('',(-27.2292328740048,0.,-1.13397459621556));
#798=VERTEX_POINT('',#797);
#799=EDGE_CURVE('E242',#798,#798,#796,.T.);
#800=ORIENTED_EDGE('',*,*,#799,.T.);
#801=EDGE_LOOP('',(#800));
#802=FACE_BOUND('',#801,.T.);
#803=ADVANCED_FACE('F278',(#791,#802),#780,.T.);
#804=CARTESIAN_POINT('',(0.,0.,0.));
#805=DIRECTION('',(1.,0.,0.));
#806=DIRECTION('',(0.,0.,-1.));
#807=AXIS2_PLACEMENT_3D('',#804,#805,#806);
#808=CYLINDRICAL_SURFACE('',#807,0.999999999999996);
#809=CARTESIAN_POINT('',(-42.75,0.,0.));
#810=DIRECTION('',(1.,0.,0.));
#811=DIRECTION('',(0.,0.,-1.));
#812=AXIS2_PLACEMENT_3D('',#809,#810,#811);
#813=CIRCLE('',#812,0.999999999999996);
#814=CARTESIAN_POINT('',(-42.75,0.,-0.999999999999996));
#815=VERTEX_POINT('',#814);
#816=EDGE_CURVE('E236',#815,#815,#813,.T.);
#817=ORIENTED_EDGE('',*,*,#816,.T.);
#818=EDGE_LOOP('',(#817));
#819=FACE_BOUND('',#818,.T.);
#820=CARTESIAN_POINT('',(-27.7292328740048,0.,0.));
#821=DIRECTION('',(1.,0.,0.));
#822=DIRECTION('',(0.,0.,-1.));
#823=AXIS2_PLACEMENT_3D('',#820,#821,#822);
#824=CIRCLE('',#823,0.999999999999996);
#825=CARTESIAN_POINT('',(-27.7292328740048,0.,-0.999999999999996));
#826=VERTEX_POINT('',#825);
#827=EDGE_CURVE('E239',#826,#826,#824,.F.);
#828=ORIENTED_EDGE('',*,*,#827,.T.);
#829=EDGE_LOOP('',(#828));
#830=FACE_BOUND('',#829,.T.);
#831=ADVANCED_FACE('F819',(#819,#830),#808,.T.);
#832=CARTESIAN_POINT('',(-42.85,0.999999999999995,0.));
#833=DIRECTION('',(1.,0.,0.));
#834=DIRECTION('',(0.,0.,-1.));
#835=AXIS2_PLACEMENT_3D('',#832,#833,#834);
#836=PLANE('',#835);
#837=CARTESIAN_POINT('',(-42.85,0.,0.));
#838=DIRECTION('',(1.,0.,0.));
#839=DIRECTION('',(0.,0.,-1.));
#840=AXIS2_PLACEMENT_3D('',#837,#838,#839);
#841=CIRCLE('',#840,1.6859375);
#842=CARTESIAN_POINT('',(-42.85,0.,-1.6859375));
#843=VERTEX_POINT('',#842);
#844=EDGE_CURVE('E72',#843,#843,#841,.T.);
#845=ORIENTED_EDGE('',*,*,#844,.T.);
#846=EDGE_LOOP('',(#845));
#847=FACE_BOUND('',#846,.T.);
#848=CARTESIAN_POINT('',(-42.85,0.,0.));
#849=DIRECTION('',(1.,0.,0.));
#850=DIRECTION('',(0.,0.,-1.));
#851=AXIS2_PLACEMENT_3D('',#848,#849,#850);
#852=CIRCLE('',#851,1.1);
#853=CARTESIAN_POINT('',(-42.85,0.,-1.1));
#854=VERTEX_POINT('',#853);
#855=EDGE_CURVE('E233',#854,#854,#852,.F.);
#856=ORIENTED_EDGE('',*,*,#855,.T.);
#857=EDGE_LOOP('',(#856));
#858=FACE_BOUND('',#857,.T.);
#859=ADVANCED_FACE('F810',(#847,#858),#836,.T.);
#860=CARTESIAN_POINT('',(0.,0.,0.));
#861=DIRECTION('',(1.,0.,0.));
#862=DIRECTION('',(0.,0.,-1.));
#863=AXIS2_PLACEMENT_3D('',#860,#861,#862);
#864=CYLINDRICAL_SURFACE('',#863,1.7859375);
#865=CARTESIAN_POINT('',(-44.0585786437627,0.,0.));
#866=DIRECTION('',(-1.,0.,0.));
#867=DIRECTION('',(0.,0.,1.));
#868=AXIS2_PLACEMENT_3D('',#865,#866,#867);
#869=CIRCLE('',#868,1.7859375);
#870=CARTESIAN_POINT('',(-44.0585786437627,0.,1.7859375));
#871=VERTEX_POINT('',#870);
#872=EDGE_CURVE('E75',#871,#871,#869,.F.);
#873=ORIENTED_EDGE('',*,*,#872,.T.);
#874=EDGE_LOOP('',(#873));
#875=FACE_BOUND('',#874,.T.);
#876=CARTESIAN_POINT('',(-42.95,0.,0.));
#877=DIRECTION('',(1.,0.,0.));
#878=DIRECTION('',(0.,0.,-1.));
#879=AXIS2_PLACEMENT_3D('',#876,#877,#878);
#880=CIRCLE('',#879,1.7859375);
#881=CARTESIAN_POINT('',(-42.95,0.,-1.7859375));
#882=VERTEX_POINT('',#881);
#883=EDGE_CURVE('E78',#882,#882,#880,.F.);
#884=ORIENTED_EDGE('',*,*,#883,.T.);
#885=EDGE_LOOP('',(#884));
#886=FACE_BOUND('',#885,.T.);
#887=ADVANCED_FACE('F801',(#875,#886),#864,.T.);
#888=CARTESIAN_POINT('',(-44.85,1.7859375,0.));
#889=DIRECTION('',(-1.,0.,0.));
#890=DIRECTION('',(0.,0.,1.));
#891=AXIS2_PLACEMENT_3D('',#888,#889,#890);
#892=PLANE('',#891);
#893=CARTESIAN_POINT('',(-44.85,0.,0.));
#894=DIRECTION('',(-1.,0.,0.));
#895=DIRECTION('',(0.,0.,1.));
#896=AXIS2_PLACEMENT_3D('',#893,#894,#895);
#897=CIRCLE('',#896,0.994516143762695);
#898=CARTESIAN_POINT('',(-44.85,0.,0.994516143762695));
#899=VERTEX_POINT('',#898);
#900=EDGE_CURVE('E97',#899,#899,#897,.T.);
#901=ORIENTED_EDGE('',*,*,#900,.T.);
#902=EDGE_LOOP('',(#901));
#903=FACE_BOUND('',#902,.T.);
#904=ADVANCED_FACE('F298',(#903),#892,.T.);
#905=CARTESIAN_POINT('',(7.7,0.,0.));
#906=DIRECTION('',(-1.,0.,0.));
#907=DIRECTION('',(0.,0.,1.));
#908=AXIS2_PLACEMENT_3D('',#905,#906,#907);
#909=TOROIDAL_SURFACE('',#908,2.,1.);
#910=CARTESIAN_POINT('',(8.69585919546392,0.,0.));
#911=DIRECTION('',(-1.,0.,0.));
#912=DIRECTION('',(0.,0.,1.));
#913=AXIS2_PLACEMENT_3D('',#910,#911,#912);
#914=CIRCLE('',#913,1.90909090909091);
#915=CARTESIAN_POINT('',(8.69585919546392,0.,1.90909090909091));
#916=VERTEX_POINT('',#915);
#917=EDGE_CURVE('E106',#916,#916,#914,.T.);
#918=ORIENTED_EDGE('',*,*,#917,.T.);
#919=EDGE_LOOP('',(#918));
#920=FACE_BOUND('',#919,.T.);
#921=ORIENTED_EDGE('',*,*,#188,.F.);
#922=EDGE_LOOP('',(#921));
#923=FACE_BOUND('',#922,.T.);
#924=ADVANCED_FACE('F294',(#920,#923),#909,.F.);
#925=CARTESIAN_POINT('',(2.,0.,0.));
#926=DIRECTION('',(1.,0.,0.));
#927=DIRECTION('',(0.,0.,-1.));
#928=AXIS2_PLACEMENT_3D('',#925,#926,#927);
#929=TOROIDAL_SURFACE('',#928,2.,1.);
#930=CARTESIAN_POINT('',(1.00414080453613,0.,0.));
#931=DIRECTION('',(1.,0.,0.));
#932=DIRECTION('',(0.,0.,-1.));
#933=AXIS2_PLACEMENT_3D('',#930,#931,#932);
#934=CIRCLE('',#933,1.90909090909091);
#935=CARTESIAN_POINT('',(1.00414080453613,0.,-1.90909090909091));
#936=VERTEX_POINT('',#935);
#937=EDGE_CURVE('E127',#936,#936,#934,.T.);
#938=ORIENTED_EDGE('',*,*,#937,.T.);
#939=EDGE_LOOP('',(#938));
#940=FACE_BOUND('',#939,.T.);
#941=ORIENTED_EDGE('',*,*,#199,.F.);
#942=EDGE_LOOP('',(#941));
#943=FACE_BOUND('',#942,.T.);
#944=ADVANCED_FACE('F297',(#940,#943),#929,.F.);
#945=CARTESIAN_POINT('',(-2.,0.,0.));
#946=DIRECTION('',(-1.,0.,0.));
#947=DIRECTION('',(0.,0.,1.));
#948=AXIS2_PLACEMENT_3D('',#945,#946,#947);
#949=TOROIDAL_SURFACE('',#948,2.,1.);
#950=CARTESIAN_POINT('',(-1.00414080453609,0.,0.));
#951=DIRECTION('',(-1.,0.,0.));
#952=DIRECTION('',(0.,0.,1.));
#953=AXIS2_PLACEMENT_3D('',#950,#951,#952);
#954=CIRCLE('',#953,1.90909090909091);
#955=CARTESIAN_POINT('',(-1.00414080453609,0.,1.90909090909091));
#956=VERTEX_POINT('',#955);
#957=EDGE_CURVE('E130',#956,#956,#954,.T.);
#958=ORIENTED_EDGE('',*,*,#957,.T.);
#959=EDGE_LOOP('',(#958));
#960=FACE_BOUND('',#959,.T.);
#961=ORIENTED_EDGE('',*,*,#356,.F.);
#962=EDGE_LOOP('',(#961));
#963=FACE_BOUND('',#962,.T.);
#964=ADVANCED_FACE('F302',(#960,#963),#949,.F.);
#965=CARTESIAN_POINT('',(-7.5,0.,0.));
#966=DIRECTION('',(1.,0.,0.));
#967=DIRECTION('',(0.,0.,-1.));
#968=AXIS2_PLACEMENT_3D('',#965,#966,#967);
#969=TOROIDAL_SURFACE('',#968,2.,1.);
#970=CARTESIAN_POINT('',(-8.49585919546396,0.,0.));
#971=DIRECTION('',(1.,0.,0.));
#972=DIRECTION('',(0.,0.,-1.));
#973=AXIS2_PLACEMENT_3D('',#970,#971,#972);
#974=CIRCLE('',#973,1.9090909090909);
#975=CARTESIAN_POINT('',(-8.49585919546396,0.,-1.9090909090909));
#976=VERTEX_POINT('',#975);
#977=EDGE_CURVE('E151',#976,#976,#974,.T.);
#978=ORIENTED_EDGE('',*,*,#977,.T.);
#979=EDGE_LOOP('',(#978));
#980=FACE_BOUND('',#979,.T.);
#981=ORIENTED_EDGE('',*,*,#367,.F.);
#982=EDGE_LOOP('',(#981));
#983=FACE_BOUND('',#982,.T.);
#984=ADVANCED_FACE('F306',(#980,#983),#969,.F.);
#985=CARTESIAN_POINT('',(-27.7292328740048,0.,0.));
#986=DIRECTION('',(1.,0.,0.));
#987=DIRECTION('',(0.,0.,-1.));
#988=AXIS2_PLACEMENT_3D('',#985,#986,#987);
#989=TOROIDAL_SURFACE('',#988,2.,1.);
#990=ORIENTED_EDGE('',*,*,#827,.F.);
#991=EDGE_LOOP('',(#990));
#992=FACE_BOUND('',#991,.T.);
#993=ORIENTED_EDGE('',*,*,#799,.F.);
#994=EDGE_LOOP('',(#993));
#995=FACE_BOUND('',#994,.T.);
#996=ADVANCED_FACE('F310',(#992,#995),#989,.F.);
#997=CARTESIAN_POINT('',(-42.75,0.,0.));
#998=DIRECTION('',(1.,0.,0.));
#999=DIRECTION('',(0.,0.,-1.));
#1000=AXIS2_PLACEMENT_3D('',#997,#998,#999);
#1001=TOROIDAL_SURFACE('',#1000,1.1,0.1);
#1002=ORIENTED_EDGE('',*,*,#855,.F.);
#1003=EDGE_LOOP('',(#1002));
#1004=FACE_BOUND('',#1003,.T.);
#1005=ORIENTED_EDGE('',*,*,#816,.F.);
#1006=EDGE_LOOP('',(#1005));
#1007=FACE_BOUND('',#1006,.T.);
#1008=ADVANCED_FACE('F314',(#1004,#1007),#1001,.F.);
#1009=CARTESIAN_POINT('',(-15.7,0.,0.));
#1010=DIRECTION('',(1.,0.,0.));
#1011=DIRECTION('',(0.,0.,-1.));
#1012=AXIS2_PLACEMENT_3D('',#1009,#1010,#1011);
#1013=TOROIDAL_SURFACE('',#1012,1.275,0.1);
#1014=ORIENTED_EDGE('',*,*,#591,.F.);
#1015=EDGE_LOOP('',(#1014));
#1016=FACE_BOUND('',#1015,.T.);
#1017=ORIENTED_EDGE('',*,*,#552,.F.);
#1018=EDGE_LOOP('',(#1017));
#1019=FACE_BOUND('',#1018,.T.);
#1020=ADVANCED_FACE('F318',(#1016,#1019),#1013,.F.);
#1021=CARTESIAN_POINT('',(-14.7,0.,0.));
#1022=DIRECTION('',(-1.,0.,0.));
#1023=DIRECTION('',(0.,0.,1.));
#1024=AXIS2_PLACEMENT_3D('',#1021,#1022,#1023);
#1025=TOROIDAL_SURFACE('',#1024,1.275,0.1);
#1026=ORIENTED_EDGE('',*,*,#563,.F.);
#1027=EDGE_LOOP('',(#1026));
#1028=FACE_BOUND('',#1027,.T.);
#1029=ORIENTED_EDGE('',*,*,#535,.F.);
#1030=EDGE_LOOP('',(#1029));
#1031=FACE_BOUND('',#1030,.T.);
#1032=ADVANCED_FACE('F322',(#1028,#1031),#1025,.F.);
#1033=CARTESIAN_POINT('',(-10.,0.,0.));
#1034=DIRECTION('',(1.,0.,0.));
#1035=DIRECTION('',(0.,0.,-1.));
#1036=AXIS2_PLACEMENT_3D('',#1033,#1034,#1035);
#1037=TOROIDAL_SURFACE('',#1036,1.275,0.1);
#1038=ORIENTED_EDGE('',*,*,#479,.F.);
#1039=EDGE_LOOP('',(#1038));
#1040=FACE_BOUND('',#1039,.T.);
#1041=ORIENTED_EDGE('',*,*,#440,.F.);
#1042=EDGE_LOOP('',(#1041));
#1043=FACE_BOUND('',#1042,.T.);
#1044=ADVANCED_FACE('F326',(#1040,#1043),#1037,.F.);
#1045=CARTESIAN_POINT('',(-9.,0.,0.));
#1046=DIRECTION('',(-1.,0.,0.));
#1047=DIRECTION('',(0.,0.,1.));
#1048=AXIS2_PLACEMENT_3D('',#1045,#1046,#1047);
#1049=TOROIDAL_SURFACE('',#1048,1.275,0.1);
#1050=ORIENTED_EDGE('',*,*,#451,.F.);
#1051=EDGE_LOOP('',(#1050));
#1052=FACE_BOUND('',#1051,.T.);
#1053=ORIENTED_EDGE('',*,*,#423,.F.);
#1054=EDGE_LOOP('',(#1053));
#1055=FACE_BOUND('',#1054,.T.);
#1056=ADVANCED_FACE('F330',(#1052,#1055),#1049,.F.);
#1057=CARTESIAN_POINT('',(-0.5,0.,0.));
#1058=DIRECTION('',(1.,0.,0.));
#1059=DIRECTION('',(0.,0.,-1.));
#1060=AXIS2_PLACEMENT_3D('',#1057,#1058,#1059);
#1061=TOROIDAL_SURFACE('',#1060,1.275,0.1);
#1062=ORIENTED_EDGE('',*,*,#311,.F.);
#1063=EDGE_LOOP('',(#1062));
#1064=FACE_BOUND('',#1063,.T.);
#1065=ORIENTED_EDGE('',*,*,#272,.F.);
#1066=EDGE_LOOP('',(#1065));
#1067=FACE_BOUND('',#1066,.T.);
#1068=ADVANCED_FACE('F334',(#1064,#1067),#1061,.F.);
#1069=CARTESIAN_POINT('',(0.5,0.,0.));
#1070=DIRECTION('',(-1.,0.,0.));
#1071=DIRECTION('',(0.,0.,1.));
#1072=AXIS2_PLACEMENT_3D('',#1069,#1070,#1071);
#1073=TOROIDAL_SURFACE('',#1072,1.275,0.1);
#1074=ORIENTED_EDGE('',*,*,#283,.F.);
#1075=EDGE_LOOP('',(#1074));
#1076=FACE_BOUND('',#1075,.T.);
#1077=ORIENTED_EDGE('',*,*,#255,.F.);
#1078=EDGE_LOOP('',(#1077));
#1079=FACE_BOUND('',#1078,.T.);
#1080=ADVANCED_FACE('F338',(#1076,#1079),#1073,.F.);
#1081=CARTESIAN_POINT('',(9.2,0.,0.));
#1082=DIRECTION('',(1.,0.,0.));
#1083=DIRECTION('',(0.,0.,-1.));
#1084=AXIS2_PLACEMENT_3D('',#1081,#1082,#1083);
#1085=TOROIDAL_SURFACE('',#1084,1.275,0.1);
#1086=ORIENTED_EDGE('',*,*,#143,.F.);
#1087=EDGE_LOOP('',(#1086));
#1088=FACE_BOUND('',#1087,.T.);
#1089=ORIENTED_EDGE('',*,*,#104,.F.);
#1090=EDGE_LOOP('',(#1089));
#1091=FACE_BOUND('',#1090,.T.);
#1092=ADVANCED_FACE('F342',(#1088,#1091),#1085,.F.);
#1093=CARTESIAN_POINT('',(10.2,0.,0.));
#1094=DIRECTION('',(-1.,0.,0.));
#1095=DIRECTION('',(0.,0.,1.));
#1096=AXIS2_PLACEMENT_3D('',#1093,#1094,#1095);
#1097=TOROIDAL_SURFACE('',#1096,1.275,0.1);
#1098=ORIENTED_EDGE('',*,*,#115,.F.);
#1099=EDGE_LOOP('',(#1098));
#1100=FACE_BOUND('',#1099,.T.);
#1101=ORIENTED_EDGE('',*,*,#87,.F.);
#1102=EDGE_LOOP('',(#1101));
#1103=FACE_BOUND('',#1102,.T.);
#1104=ADVANCED_FACE('F346',(#1100,#1103),#1097,.F.);
#1105=CARTESIAN_POINT('',(-21.6676158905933,0.,0.));
#1106=DIRECTION('',(1.,0.,0.));
#1107=DIRECTION('',(0.,0.,-1.));
#1108=AXIS2_PLACEMENT_3D('',#1105,#1106,#1107);
#1109=TOROIDAL_SURFACE('',#1108,2.0359375,0.25);
#1110=ORIENTED_EDGE('',*,*,#675,.F.);
#1111=EDGE_LOOP('',(#1110));
#1112=FACE_BOUND('',#1111,.T.);
#1113=ORIENTED_EDGE('',*,*,#647,.F.);
#1114=EDGE_LOOP('',(#1113));
#1115=FACE_BOUND('',#1114,.T.);
#1116=ADVANCED_FACE('F350',(#1112,#1115),#1109,.F.);
#1117=CARTESIAN_POINT('',(-44.1,0.,0.));
#1118=DIRECTION('',(1.,0.,0.));
#1119=DIRECTION('',(0.,0.,-1.));
#1120=AXIS2_PLACEMENT_3D('',#1117,#1118,#1119);
#1121=CONICAL_SURFACE('',#1120,1.7859375,0.785398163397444);
#1122=CARTESIAN_POINT('',(-44.8207106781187,0.,0.));
#1123=DIRECTION('',(-1.,0.,0.));
#1124=DIRECTION('',(0.,0.,1.));
#1125=AXIS2_PLACEMENT_3D('',#1122,#1123,#1124);
#1126=CIRCLE('',#1125,1.06522682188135);
#1127=CARTESIAN_POINT('',(-44.8207106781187,0.,1.06522682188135));
#1128=VERTEX_POINT('',#1127);
#1129=EDGE_CURVE('E91',#1128,#1128,#1126,.F.);
#1130=ORIENTED_EDGE('',*,*,#1129,.T.);
#1131=EDGE_LOOP('',(#1130));
#1132=FACE_BOUND('',#1131,.T.);
#1133=CARTESIAN_POINT('',(-44.1292893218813,0.,0.));
#1134=DIRECTION('',(-1.,0.,0.));
#1135=DIRECTION('',(0.,0.,1.));
#1136=AXIS2_PLACEMENT_3D('',#1133,#1134,#1135);
#1137=CIRCLE('',#1136,1.75664817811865);
#1138=CARTESIAN_POINT('',(-44.1292893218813,0.,1.75664817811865));
#1139=VERTEX_POINT('',#1138);
#1140=EDGE_CURVE('E94',#1139,#1139,#1137,.T.);
#1141=ORIENTED_EDGE('',*,*,#1140,.T.);
#1142=EDGE_LOOP('',(#1141));
#1143=FACE_BOUND('',#1142,.T.);
#1144=ADVANCED_FACE('F354',(#1132,#1143),#1121,.T.);
#1145=CARTESIAN_POINT('',(12.15,0.,0.));
#1146=DIRECTION('',(-1.,0.,0.));
#1147=DIRECTION('',(0.,0.,1.));
#1148=AXIS2_PLACEMENT_3D('',#1145,#1146,#1147);
#1149=CONICAL_SURFACE('',#1148,1.5,0.785398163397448);
#1150=CARTESIAN_POINT('',(11.9428932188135,0.,0.));
#1151=DIRECTION('',(1.,0.,0.));
#1152=DIRECTION('',(0.,0.,-1.));
#1153=AXIS2_PLACEMENT_3D('',#1150,#1151,#1152);
#1154=CIRCLE('',#1153,1.70710678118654);
#1155=CARTESIAN_POINT('',(11.9428932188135,0.,-1.70710678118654));
#1156=VERTEX_POINT('',#1155);
#1157=EDGE_CURVE('E10',#1156,#1156,#1154,.T.);
#1158=ORIENTED_EDGE('',*,*,#1157,.T.);
#1159=EDGE_LOOP('',(#1158));
#1160=FACE_BOUND('',#1159,.T.);
#1161=CARTESIAN_POINT('',(12.1207106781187,0.,0.));
#1162=DIRECTION('',(1.,0.,0.));
#1163=DIRECTION('',(0.,0.,-1.));
#1164=AXIS2_PLACEMENT_3D('',#1161,#1162,#1163);
#1165=CIRCLE('',#1164,1.52928932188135);
#1166=CARTESIAN_POINT('',(12.1207106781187,0.,-1.52928932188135));
#1167=VERTEX_POINT('',#1166);
#1168=EDGE_CURVE('E100',#1167,#1167,#1165,.F.);
#1169=ORIENTED_EDGE('',*,*,#1168,.T.);
#1170=EDGE_LOOP('',(#1169));
#1171=FACE_BOUND('',#1170,.T.);
#1172=ADVANCED_FACE('F358',(#1160,#1171),#1149,.T.);
#1173=CARTESIAN_POINT('',(-21.3085786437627,0.,0.));
#1174=DIRECTION('',(-1.,0.,0.));
#1175=DIRECTION('',(0.,0.,1.));
#1176=AXIS2_PLACEMENT_3D('',#1173,#1174,#1175);
#1177=TOROIDAL_SURFACE('',#1176,1.9,0.1);
#1178=ORIENTED_EDGE('',*,*,#636,.F.);
#1179=EDGE_LOOP('',(#1178));
#1180=FACE_BOUND('',#1179,.T.);
#1181=ORIENTED_EDGE('',*,*,#608,.F.);
#1182=EDGE_LOOP('',(#1181));
#1183=FACE_BOUND('',#1182,.T.);
#1184=ADVANCED_FACE('F362',(#1180,#1183),#1177,.T.);
#1185=CARTESIAN_POINT('',(-10.2,0.,0.));
#1186=DIRECTION('',(1.,0.,0.));
#1187=DIRECTION('',(0.,0.,-1.));
#1188=AXIS2_PLACEMENT_3D('',#1185,#1186,#1187);
#1189=TOROIDAL_SURFACE('',#1188,1.9,0.1);
#1190=ORIENTED_EDGE('',*,*,#496,.F.);
#1191=EDGE_LOOP('',(#1190));
#1192=FACE_BOUND('',#1191,.T.);
#1193=ORIENTED_EDGE('',*,*,#468,.F.);
#1194=EDGE_LOOP('',(#1193));
#1195=FACE_BOUND('',#1194,.T.);
#1196=ADVANCED_FACE('F365',(#1192,#1195),#1189,.T.);
#1197=CARTESIAN_POINT('',(-14.5,0.,0.));
#1198=DIRECTION('',(-1.,0.,0.));
#1199=DIRECTION('',(0.,0.,1.));
#1200=AXIS2_PLACEMENT_3D('',#1197,#1198,#1199);
#1201=TOROIDAL_SURFACE('',#1200,1.9,0.1);
#1202=ORIENTED_EDGE('',*,*,#524,.F.);
#1203=EDGE_LOOP('',(#1202));
#1204=FACE_BOUND('',#1203,.T.);
#1205=ORIENTED_EDGE('',*,*,#507,.F.);
#1206=EDGE_LOOP('',(#1205));
#1207=FACE_BOUND('',#1206,.T.);
#1208=ADVANCED_FACE('F369',(#1204,#1207),#1201,.T.);
#1209=CARTESIAN_POINT('',(-8.59544511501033,0.,0.));
#1210=DIRECTION('',(-1.,0.,0.));
#1211=DIRECTION('',(0.,0.,1.));
#1212=AXIS2_PLACEMENT_3D('',#1209,#1210,#1211);
#1213=TOROIDAL_SURFACE('',#1212,1.9,0.1);
#1214=ORIENTED_EDGE('',*,*,#384,.F.);
#1215=EDGE_LOOP('',(#1214));
#1216=FACE_BOUND('',#1215,.T.);
#1217=ORIENTED_EDGE('',*,*,#977,.F.);
#1218=EDGE_LOOP('',(#1217));
#1219=FACE_BOUND('',#1218,.T.);
#1220=ADVANCED_FACE('F373',(#1216,#1219),#1213,.T.);
#1221=CARTESIAN_POINT('',(-8.8,0.,0.));
#1222=DIRECTION('',(-1.,0.,0.));
#1223=DIRECTION('',(0.,0.,1.));
#1224=AXIS2_PLACEMENT_3D('',#1221,#1222,#1223);
#1225=TOROIDAL_SURFACE('',#1224,1.9,0.1);
#1226=ORIENTED_EDGE('',*,*,#412,.F.);
#1227=EDGE_LOOP('',(#1226));
#1228=FACE_BOUND('',#1227,.T.);
#1229=ORIENTED_EDGE('',*,*,#395,.F.);
#1230=EDGE_LOOP('',(#1229));
#1231=FACE_BOUND('',#1230,.T.);
#1232=ADVANCED_FACE('F377',(#1228,#1231),#1225,.T.);
#1233=CARTESIAN_POINT('',(-0.7,0.,0.));
#1234=DIRECTION('',(1.,0.,0.));
#1235=DIRECTION('',(0.,0.,-1.));
#1236=AXIS2_PLACEMENT_3D('',#1233,#1234,#1235);
#1237=TOROIDAL_SURFACE('',#1236,1.9,0.1);
#1238=ORIENTED_EDGE('',*,*,#328,.F.);
#1239=EDGE_LOOP('',(#1238));
#1240=FACE_BOUND('',#1239,.T.);
#1241=ORIENTED_EDGE('',*,*,#300,.F.);
#1242=EDGE_LOOP('',(#1241));
#1243=FACE_BOUND('',#1242,.T.);
#1244=ADVANCED_FACE('F381',(#1240,#1243),#1237,.T.);
#1245=CARTESIAN_POINT('',(-0.904554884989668,0.,0.));
#1246=DIRECTION('',(-1.,0.,0.));
#1247=DIRECTION('',(0.,0.,1.));
#1248=AXIS2_PLACEMENT_3D('',#1245,#1246,#1247);
#1249=TOROIDAL_SURFACE('',#1248,1.9,0.1);
#1250=ORIENTED_EDGE('',*,*,#957,.F.);
#1251=EDGE_LOOP('',(#1250));
#1252=FACE_BOUND('',#1251,.T.);
#1253=ORIENTED_EDGE('',*,*,#339,.F.);
#1254=EDGE_LOOP('',(#1253));
#1255=FACE_BOUND('',#1254,.T.);
#1256=ADVANCED_FACE('F385',(#1252,#1255),#1249,.T.);
#1257=CARTESIAN_POINT('',(0.904554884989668,0.,0.));
#1258=DIRECTION('',(-1.,0.,0.));
#1259=DIRECTION('',(0.,0.,1.));
#1260=AXIS2_PLACEMENT_3D('',#1257,#1258,#1259);
#1261=TOROIDAL_SURFACE('',#1260,1.9,0.1);
#1262=ORIENTED_EDGE('',*,*,#216,.F.);
#1263=EDGE_LOOP('',(#1262));
#1264=FACE_BOUND('',#1263,.T.);
#1265=ORIENTED_EDGE('',*,*,#937,.F.);
#1266=EDGE_LOOP('',(#1265));
#1267=FACE_BOUND('',#1266,.T.);
#1268=ADVANCED_FACE('F389',(#1264,#1267),#1261,.T.);
#1269=CARTESIAN_POINT('',(0.7,0.,0.));
#1270=DIRECTION('',(-1.,0.,0.));
#1271=DIRECTION('',(0.,0.,1.));
#1272=AXIS2_PLACEMENT_3D('',#1269,#1270,#1271);
#1273=TOROIDAL_SURFACE('',#1272,1.9,0.1);
#1274=ORIENTED_EDGE('',*,*,#244,.F.);
#1275=EDGE_LOOP('',(#1274));
#1276=FACE_BOUND('',#1275,.T.);
#1277=ORIENTED_EDGE('',*,*,#227,.F.);
#1278=EDGE_LOOP('',(#1277));
#1279=FACE_BOUND('',#1278,.T.);
#1280=ADVANCED_FACE('F393',(#1276,#1279),#1273,.T.);
#1281=CARTESIAN_POINT('',(9.,0.,0.));
#1282=DIRECTION('',(1.,0.,0.));
#1283=DIRECTION('',(0.,0.,-1.));
#1284=AXIS2_PLACEMENT_3D('',#1281,#1282,#1283);
#1285=TOROIDAL_SURFACE('',#1284,1.9,0.1);
#1286=ORIENTED_EDGE('',*,*,#160,.F.);
#1287=EDGE_LOOP('',(#1286));
#1288=FACE_BOUND('',#1287,.T.);
#1289=ORIENTED_EDGE('',*,*,#132,.F.);
#1290=EDGE_LOOP('',(#1289));
#1291=FACE_BOUND('',#1290,.T.);
#1292=ADVANCED_FACE('F397',(#1288,#1291),#1285,.T.);
#1293=CARTESIAN_POINT('',(8.79544511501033,0.,0.));
#1294=DIRECTION('',(-1.,0.,0.));
#1295=DIRECTION('',(0.,0.,1.));
#1296=AXIS2_PLACEMENT_3D('',#1293,#1294,#1295);
#1297=TOROIDAL_SURFACE('',#1296,1.9,0.1);
#1298=ORIENTED_EDGE('',*,*,#917,.F.);
#1299=EDGE_LOOP('',(#1298));
#1300=FACE_BOUND('',#1299,.T.);
#1301=ORIENTED_EDGE('',*,*,#171,.F.);
#1302=EDGE_LOOP('',(#1301));
#1303=FACE_BOUND('',#1302,.T.);
#1304=ADVANCED_FACE('F401',(#1300,#1303),#1297,.T.);
#1305=CARTESIAN_POINT('',(12.05,0.,0.));
#1306=DIRECTION('',(1.,0.,0.));
#1307=DIRECTION('',(0.,0.,-1.));
#1308=AXIS2_PLACEMENT_3D('',#1305,#1306,#1307);
#1309=TOROIDAL_SURFACE('',#1308,1.45857864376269,0.1);
#1310=ORIENTED_EDGE('',*,*,#1168,.F.);
#1311=EDGE_LOOP('',(#1310));
#1312=FACE_BOUND('',#1311,.T.);
#1313=ORIENTED_EDGE('',*,*,#31,.F.);
#1314=EDGE_LOOP('',(#1313));
#1315=FACE_BOUND('',#1314,.T.);
#1316=ADVANCED_FACE('F405',(#1312,#1315),#1309,.T.);
#1317=CARTESIAN_POINT('',(-44.75,0.,0.));
#1318=DIRECTION('',(-1.,0.,0.));
#1319=DIRECTION('',(0.,0.,1.));
#1320=AXIS2_PLACEMENT_3D('',#1317,#1318,#1319);
#1321=TOROIDAL_SURFACE('',#1320,0.994516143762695,0.1);
#1322=ORIENTED_EDGE('',*,*,#1129,.F.);
#1323=EDGE_LOOP('',(#1322));
#1324=FACE_BOUND('',#1323,.T.);
#1325=ORIENTED_EDGE('',*,*,#900,.F.);
#1326=EDGE_LOOP('',(#1325));
#1327=FACE_BOUND('',#1326,.T.);
#1328=ADVANCED_FACE('F409',(#1324,#1327),#1321,.T.);
#1329=CARTESIAN_POINT('',(-26.0732050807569,0.,0.));
#1330=DIRECTION('',(-1.,0.,0.));
#1331=DIRECTION('',(0.,0.,1.));
#1332=AXIS2_PLACEMENT_3D('',#1329,#1330,#1331);
#1333=TOROIDAL_SURFACE('',#1332,1.6859375,0.1);
#1334=ORIENTED_EDGE('',*,*,#788,.F.);
#1335=EDGE_LOOP('',(#1334));
#1336=FACE_BOUND('',#1335,.T.);
#1337=ORIENTED_EDGE('',*,*,#760,.F.);
#1338=EDGE_LOOP('',(#1337));
#1339=FACE_BOUND('',#1338,.T.);
#1340=ADVANCED_FACE('F413',(#1336,#1339),#1333,.T.);
#1341=CARTESIAN_POINT('',(-44.0585786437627,0.,0.));
#1342=DIRECTION('',(-1.,0.,0.));
#1343=DIRECTION('',(0.,0.,1.));
#1344=AXIS2_PLACEMENT_3D('',#1341,#1342,#1343);
#1345=TOROIDAL_SURFACE('',#1344,1.6859375,0.1);
#1346=ORIENTED_EDGE('',*,*,#1140,.F.);
#1347=EDGE_LOOP('',(#1346));
#1348=FACE_BOUND('',#1347,.T.);
#1349=ORIENTED_EDGE('',*,*,#872,.F.);
#1350=EDGE_LOOP('',(#1349));
#1351=FACE_BOUND('',#1350,.T.);
#1352=ADVANCED_FACE('F417',(#1348,#1351),#1345,.T.);
#1353=CARTESIAN_POINT('',(-42.95,0.,0.));
#1354=DIRECTION('',(1.,0.,0.));
#1355=DIRECTION('',(0.,0.,-1.));
#1356=AXIS2_PLACEMENT_3D('',#1353,#1354,#1355);
#1357=TOROIDAL_SURFACE('',#1356,1.6859375,0.1);
#1358=ORIENTED_EDGE('',*,*,#883,.F.);
#1359=EDGE_LOOP('',(#1358));
#1360=FACE_BOUND('',#1359,.T.);
#1361=ORIENTED_EDGE('',*,*,#844,.F.);
#1362=EDGE_LOOP('',(#1361));
#1363=FACE_BOUND('',#1362,.T.);
#1364=ADVANCED_FACE('F421',(#1360,#1363),#1357,.T.);
#1365=CARTESIAN_POINT('',(-23.4,0.,0.));
#1366=DIRECTION('',(1.,0.,0.));
#1367=DIRECTION('',(0.,0.,-1.));
#1368=AXIS2_PLACEMENT_3D('',#1365,#1366,#1367);
#1369=TOROIDAL_SURFACE('',#1368,1.6859375,0.1);
#1370=ORIENTED_EDGE('',*,*,#771,.F.);
#1371=EDGE_LOOP('',(#1370));
#1372=FACE_BOUND('',#1371,.T.);
#1373=ORIENTED_EDGE('',*,*,#740,.F.);
#1374=EDGE_LOOP('',(#1373));
#1375=FACE_BOUND('',#1374,.T.);
#1376=ADVANCED_FACE('F425',(#1372,#1375),#1369,.T.);
#1377=CARTESIAN_POINT('',(-22.75,0.,0.));
#1378=DIRECTION('',(-1.,0.,0.));
#1379=DIRECTION('',(0.,0.,1.));
#1380=AXIS2_PLACEMENT_3D('',#1377,#1378,#1379);
#1381=TOROIDAL_SURFACE('',#1380,1.6859375,0.1);
#1382=ORIENTED_EDGE('',*,*,#692,.F.);
#1383=EDGE_LOOP('',(#1382));
#1384=FACE_BOUND('',#1383,.T.);
#1385=ORIENTED_EDGE('',*,*,#664,.F.);
#1386=EDGE_LOOP('',(#1385));
#1387=FACE_BOUND('',#1386,.T.);
#1388=ADVANCED_FACE('F429',(#1384,#1387),#1381,.T.);
#1389=CARTESIAN_POINT('',(-15.9,0.,0.));
#1390=DIRECTION('',(1.,0.,0.));
#1391=DIRECTION('',(0.,0.,-1.));
#1392=AXIS2_PLACEMENT_3D('',#1389,#1390,#1391);
#1393=TOROIDAL_SURFACE('',#1392,1.9,0.1);
#1394=ORIENTED_EDGE('',*,*,#619,.F.);
#1395=EDGE_LOOP('',(#1394));
#1396=FACE_BOUND('',#1395,.T.);
#1397=ORIENTED_EDGE('',*,*,#580,.F.);
#1398=EDGE_LOOP('',(#1397));
#1399=FACE_BOUND('',#1398,.T.);
#1400=ADVANCED_FACE('F433',(#1396,#1399),#1393,.T.);
#1401=CARTESIAN_POINT('',(10.4,0.,0.));
#1402=DIRECTION('',(-1.,0.,0.));
#1403=DIRECTION('',(0.,0.,1.));
#1404=AXIS2_PLACEMENT_3D('',#1401,#1402,#1403);
#1405=TOROIDAL_SURFACE('',#1404,1.9,0.1);
#1406=ORIENTED_EDGE('',*,*,#76,.F.);
#1407=EDGE_LOOP('',(#1406));
#1408=FACE_BOUND('',#1407,.T.);
#1409=ORIENTED_EDGE('',*,*,#59,.F.);
#1410=EDGE_LOOP('',(#1409));
#1411=FACE_BOUND('',#1410,.T.);
#1412=ADVANCED_FACE('F436',(#1408,#1411),#1405,.T.);
#1413=CARTESIAN_POINT('',(11.2357864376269,0.,0.));
#1414=DIRECTION('',(1.,0.,0.));
#1415=DIRECTION('',(0.,0.,-1.));
#1416=AXIS2_PLACEMENT_3D('',#1413,#1414,#1415);
#1417=DEGENERATE_TOROIDAL_SURFACE('',#1416,0.999999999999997,1.,.T.);
#1418=ORIENTED_EDGE('',*,*,#1157,.F.);
#1419=EDGE_LOOP('',(#1418));
#1420=FACE_BOUND('',#1419,.T.);
#1421=ORIENTED_EDGE('',*,*,#48,.F.);
#1422=EDGE_LOOP('',(#1421));
#1423=FACE_BOUND('',#1422,.T.);
#1424=ADVANCED_FACE('F39',(#1420,#1423),#1417,.T.);
#1425=CLOSED_SHELL('',(#35,#63,#91,#119,#147,#175,#203,#231,#259,#287,#315,#343,#371,#399,#427,
#455,#483,#511,#539,#567,#595,#623,#651,#679,#707,#727,#747,#775,#803,#831,#859,#887,#904,#924,
#944,#964,#984,#996,#1008,#1020,#1032,#1044,#1056,#1068,#1080,#1092,#1104,#1116,#1144,#1172,
#1184,#1196,#1208,#1220,#1232,#1244,#1256,#1268,#1280,#1292,#1304,#1316,#1328,#1340,#1352,#1364,
#1376,#1388,#1400,#1412,#1424));
#1426=MANIFOLD_SOLID_BREP('B2',#1425);
#1427=ADVANCED_BREP_SHAPE_REPRESENTATION('',(#18,#1426),#14);
#1428=SHAPE_DEFINITION_REPRESENTATION(#9,#1427);
ENDSEC;
END-ISO-10303-21;
